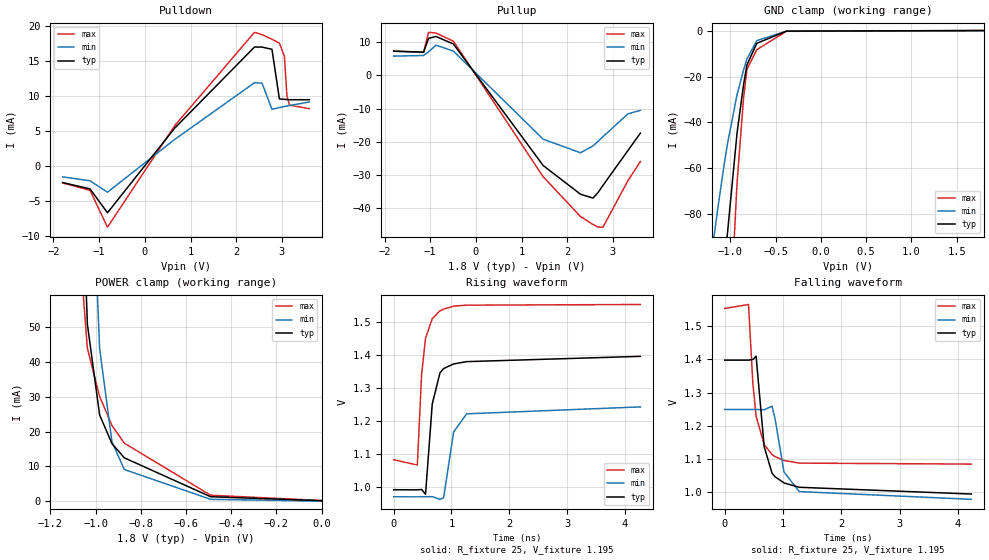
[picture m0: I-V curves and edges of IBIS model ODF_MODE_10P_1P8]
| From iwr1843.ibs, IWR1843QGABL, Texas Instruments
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|   Model Cell ODF_MODE_10P_1P8
|ODF_MODE_10P_1P8
[Model]   ODF_MODE_10P_1P8
Model_type   3-state
Polarity   Non-Inverting
Enable   Active-Low
Cref =  5pF
Rref =  25ohm
Vref =  1.2V
Vmeas = 1.2V
|   typ   min   max
C_comp   4.874558p   4.215314p   4.981964p
[Temperature Range]   25   125   -40
[Voltage Range]   1.8   1.62   1.98
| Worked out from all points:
|   slope of the pulldown table from 0 to 0.27 V, typ, clamps not added: 119 ohm
|   slope of the pullup table from 0 to 0.27 V, typ, clamps not added: 49.5 ohm
|   GND clamp passes 1 mA (typ) near -0.50 V on its own axis
|   POWER clamp passes 1 mA (typ) near -0.47 V on its own axis
|   rising waveform, R_fixture 25, V_fixture 1.195: 20-80 % time 137ps typ, 176ps min, 122ps max; typ from 0.993 V to 1.4 V
|   falling waveform, R_fixture 25, V_fixture 1.195: 20-80 % time 180ps typ, 204ps min, 155ps max; typ from 1.4 V to 0.994 V
| Where Nom  PVT is Nominal Process, 1.8V, 25C
|   Fast PVT is Strong Process,  1.98V, -40C
|   Slow PVT is Weak Process,   1.62V, 125C
[POWER_clamp]
|   voltage   I(typ)   I(min)   I(max)
-1.8V     3.242A     2.917A     3.551A
-1.109V   229.8mA    378.4mA    156.8mA
-1.091V   154.6mA    311.8mA    92.51mA
-1.073V   120.1mA    251.1mA    76.33mA
-1.055V   85.5mA     190.4mA    60.15mA
-1.036V   50.93mA    129.6mA    43.96mA
-1.018V   42.22mA    101.1mA    39.35mA
-981.8mV  24.8mA     43.91mA    30.12mA
-927.3mV  16.56mA    17.07mA    21.77mA
-872.7mV  12.47mA    9.116mA    16.69mA
-490.9mV  1.283mA    532.4uA    1.712mA
0V        136.4uA    15.76uA    197.7uA
[Pulldown]
|   voltage   I(typ)   I(min)   I(max)
-1.8V     -2.412mA   -1.6mA     -2.461mA
-1.2V     -3.318mA   -2.16mA    -3.525mA
-818.2mV  -6.733mA   -3.792mA   -8.79mA
654.5mV   5.376mA    3.76mA     5.731mA
2.4V      16.97mA    11.86mA    19.07mA
2.564V    16.96mA    11.81mA    18.74mA
2.782V    16.64mA    8.078mA    18.08mA
2.945V    9.542mA    8.304mA    17.51mA
3.055V    9.488mA    8.456mA    15.63mA
3.109V    9.457mA    8.531mA    10.02mA
3.164V    9.425mA    8.605mA    8.659mA
3.6V      9.434mA    9.109mA    8.151mA
[Pullup]
|   voltage   I(typ)   I(min)   I(max)
-1.8V     7.229mA    5.735mA    7.23mA
-1.145V   6.943mA    5.923mA    6.84mA
-1.036V   11.07mA    7.027mA    12.88mA
-872.7mV  11.63mA    9.037mA    12.68mA
-490.9mV  9.365mA    7.225mA    10.19mA
1.473V    -27.11mA   -19.21mA   -30.48mA
2.291V    -35.74mA   -23.28mA   -42.44mA
2.564V    -36.88mA   -21.22mA   -44.83mA
2.673V    -35.22mA   -19.85mA   -45.58mA
2.782V    -33.06mA   -18.44mA   -45.61mA
3.327V    -22.62mA   -11.6mA    -31.65mA
3.6V      -17.38mA   -10.55mA   -25.93mA
[GND_clamp]
|   voltage   I(typ)   I(min)   I(max)
-1.8V     -549.3mA   -299.7mA   -968.7mA
-1.4V     -297.4mA   -160.4mA   -525.2mA
-1.182V   -166.8mA   -89.91mA   -292.3mA
-1.145V   -146.1mA   -79.03mA   -255mA
-1.073V   -107.7mA   -59.22mA   -184.6mA
-1.036V   -89.6mA    -50.06mA   -151.3mA
-927.3mV  -44.72mA   -27.91mA   -66.55mA
-854.5mV  -23.35mA   -16.99mA   -29.19mA
-818.2mV  -14.94mA   -12.33mA   -16.86mA
-709.1mV  -5.45mA    -4.263mA   -8.226mA
-381.8mV  -133.2uA   -158.1uA   -207.9uA
1.8V      136.4uA    20.08uA    143.2uA
[Ramp]
| variable   typ   min   max
dV/dt_f 0.40840939/0.3157282n 0.29364345/0.37004599n 0.46867775/0.26250195n
dV/dt_r 0.40777967/0.19880521n 0.29402933/0.26664937n 0.46883574/0.17457239n
R_load = 25
[Rising Waveform]
R_fixture = 25
V_fixture = 1.195
V_fixture_min = 1.11
V_fixture_max = 1.32
|   time   V(typ)   V(min)   V(max)
0s        993mV      971.8mV    1.084V
409.9ps   992.9mV    971.7mV    1.068V
483.6ps   993.9mV    971.8mV    1.343V
551.3ps   979.4mV    971.8mV    1.452V
667.7ps   1.253V     972.3mV    1.511V
801.4ps   1.347V     964.1mV    1.535V
864.2ps   1.36V      968.9mV    1.54V
1.037ns   1.374V     1.168V     1.549V
1.262ns   1.381V     1.223V     1.552V
4.267ns   1.397V     1.244V     1.554V
[Falling Waveform]
R_fixture = 25
V_fixture = 1.195
V_fixture_min = 1.11
V_fixture_max = 1.32
|   time   V(typ)   V(min)   V(max)
0s        1.398V     1.249V     1.554V
408.2ps   1.398V     1.249V     1.566V
482.8ps   1.4V       1.249V     1.327V
538.2ps   1.41V      1.249V     1.229V
676.4ps   1.137V     1.248V     1.143V
810.6ps   1.057V     1.259V     1.113V
861.2ps   1.046V     1.223V     1.107V
1.017ns   1.027V     1.06V      1.095V
1.277ns   1.014V     1.001V     1.087V
4.229ns   993.6mV    977.6mV    1.084V
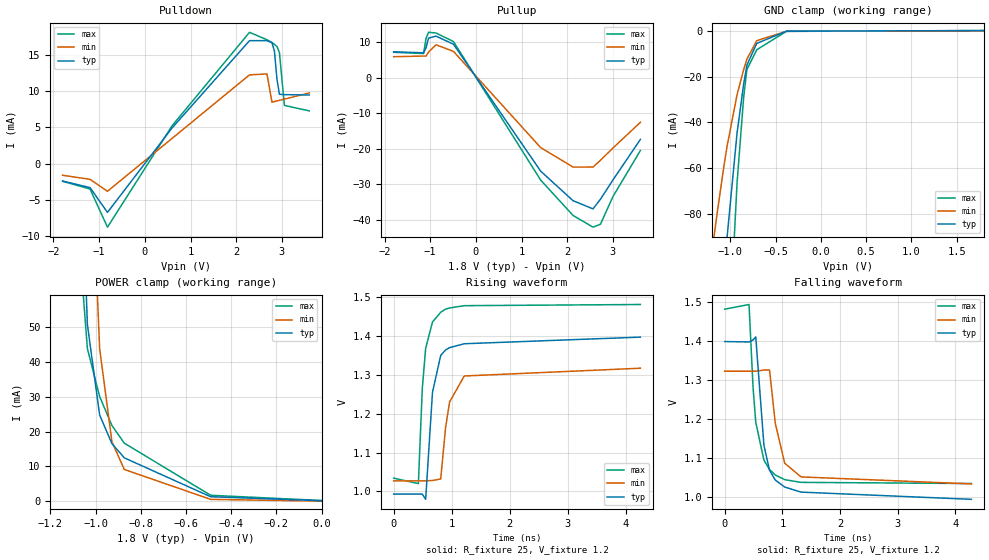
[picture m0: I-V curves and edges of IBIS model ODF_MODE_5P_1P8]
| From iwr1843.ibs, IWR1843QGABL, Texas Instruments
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|   Model Cell ODF_MODE_5P_1P8
|ODF_MODE_5P_1P8
[Model]   ODF_MODE_5P_1P8
Model_type   3-state
Polarity   Non-Inverting
Enable   Active-Low
Cref =  5pF
Rref =  25ohm
Vref =  1.2V
Vmeas = 1.2V
|   typ   min   max
C_comp   4.704305p   4.215546p   4.981964p
[Temperature Range]   25   125   -40
[Voltage Range]   1.8   1.71   1.89
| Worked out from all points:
|   slope of the pulldown table from 0 to 0.27 V, typ, clamps not added: 119 ohm
|   slope of the pullup table from 0 to 0.27 V, typ, clamps not added: 49.5 ohm
|   GND clamp passes 1 mA (typ) near -0.50 V on its own axis
|   POWER clamp passes 1 mA (typ) near -0.47 V on its own axis
|   rising waveform, R_fixture 25, V_fixture 1.2: 20-80 % time 137ps typ, 174ps min, 123ps max; typ from 0.993 V to 1.4 V
|   falling waveform, R_fixture 25, V_fixture 1.2: 20-80 % time 180ps typ, 203ps min, 156ps max; typ from 1.4 V to 0.994 V
| Where Nom  PVT is Nominal Process, 1.8V, 25C
|   Fast PVT is Strong Process,  1.89V, -40C
|   Slow PVT is Weak Process,   1.71V, 125C
[POWER_clamp]
|   voltage   I(typ)   I(min)   I(max)
-1.8V     3.242A     2.917A     3.551A
-1.109V   229.8mA    378.4mA    156.8mA
-1.091V   154.6mA    311.8mA    92.51mA
-1.073V   120.1mA    251.1mA    76.33mA
-1.055V   85.5mA     190.4mA    60.15mA
-1.036V   50.93mA    129.7mA    43.96mA
-1.018V   42.22mA    101.1mA    39.35mA
-981.8mV  24.8mA     43.93mA    30.12mA
-927.3mV  16.56mA    17.08mA    21.77mA
-872.7mV  12.47mA    9.127mA    16.69mA
-490.9mV  1.283mA    520.3uA    1.703mA
0V        136.4uA    17.39uA    192.6uA
[Pulldown]
|   voltage   I(typ)   I(min)   I(max)
-1.8V     -2.412mA   -1.618mA   -2.455mA
-1.2V     -3.318mA   -2.182mA   -3.512mA
-818.2mV  -6.733mA   -3.822mA   -8.766mA
600mV     4.933mA    3.483mA    5.232mA
2.291V    16.92mA    12.21mA    18.07mA
2.673V    16.93mA    12.34mA    17.05mA
2.782V    16.64mA    8.463mA    16.66mA
2.836V    15.51mA    8.538mA    16.41mA
2.891V    11.64mA    8.617mA    16.11mA
2.945V    9.542mA    8.7mA      15.3mA
3.055V    9.488mA    8.872mA    7.999mA
3.6V      9.434mA    9.724mA    7.245mA
[Pullup]
|   voltage   I(typ)   I(min)   I(max)
-1.8V     7.229mA    5.851mA    7.098mA
-1.145V   6.943mA    6.037mA    6.742mA
-1.091V   8.386mA    6.029mA    10.96mA
-1.036V   11.07mA    7.162mA    12.7mA
-872.7mV  11.63mA    9.202mA    12.52mA
-490.9mV  9.365mA    7.348mA    10.1mA
1.418V    -26.29mA   -19.68mA   -28.8mA
2.127V    -34.6mA    -25.15mA   -38.74mA
2.564V    -36.88mA   -25.13mA   -42.02mA
2.727V    -34.16mA   -23.23mA   -41.19mA
3V        -28.76mA   -19.79mA   -33.41mA
3.6V      -17.38mA   -12.57mA   -20.51mA
[GND_clamp]
|   voltage   I(typ)   I(min)   I(max)
-1.8V     -549.3mA   -299.7mA   -968.7mA
-1.4V     -297.4mA   -160.4mA   -525.2mA
-1.182V   -166.8mA   -89.91mA   -292.3mA
-1.145V   -146.1mA   -79.03mA   -255mA
-1.073V   -107.7mA   -59.22mA   -184.6mA
-1.036V   -89.6mA    -50.06mA   -151.3mA
-927.3mV  -44.72mA   -27.91mA   -66.54mA
-854.5mV  -23.35mA   -16.99mA   -29.19mA
-818.2mV  -14.94mA   -12.33mA   -16.85mA
-709.1mV  -5.45mA    -4.265mA   -8.219mA
-381.8mV  -133.2uA   -160.9uA   -201.8uA
1.8V      136.4uA    19.34uA    177.4uA
[Ramp]
| variable   typ   min   max
dV/dt_f  0.4084093/0.31574765n 0.31261723/0.3664154n 0.44567628/0.26426358n
dV/dt_r 0.40778038/0.19881392n 0.31285104/0.26062314n  0.4459807/0.17701337n
R_load = 25
[Rising Waveform]
R_fixture = 25
V_fixture = 1.2
V_fixture_min = 1.18
V_fixture_max = 1.26
|   time   V(typ)   V(min)   V(max)
0s        993mV      1.027V     1.034V
426.1ps   993mV      1.027V     1.02V
493.8ps   993mV      1.027V     1.265V
551.6ps   979.5mV    1.027V     1.368V
669.5ps   1.255V     1.028V     1.436V
811.2ps   1.35V      1.032V     1.461V
894.9ps   1.364V     1.164V     1.469V
964ps     1.37V      1.23V      1.472V
1.217ns   1.38V      1.297V     1.478V
4.253ns   1.397V     1.317V     1.481V
[Falling Waveform]
R_fixture = 25
V_fixture = 1.2
V_fixture_min = 1.18
V_fixture_max = 1.26
|   time   V(typ)   V(min)   V(max)
0s        1.398V     1.322V     1.481V
422.1ps   1.397V     1.322V     1.493V
491.3ps   1.402V     1.322V     1.282V
538.6ps   1.41V      1.322V     1.191V
680.5ps   1.132V     1.325V     1.094V
777.7ps   1.068V     1.325V     1.07V
876.8ps   1.043V     1.189V     1.056V
1.041ns   1.025V     1.086V     1.044V
1.324ns   1.012V     1.051V     1.037V
4.279ns   993.5mV    1.033V     1.034V
